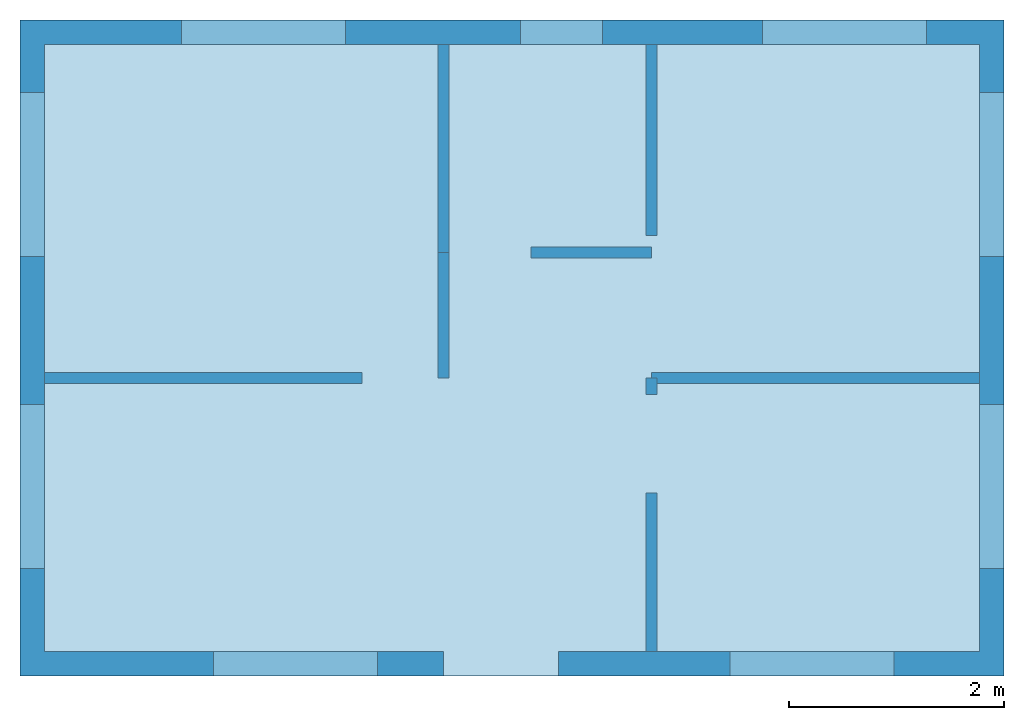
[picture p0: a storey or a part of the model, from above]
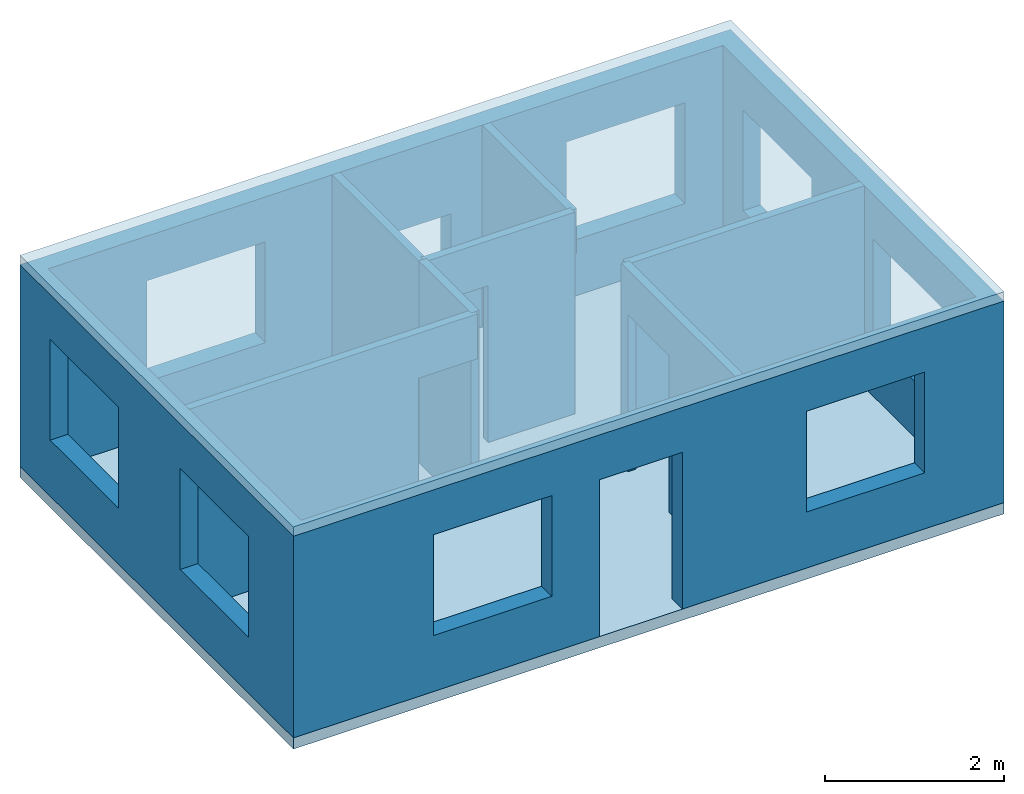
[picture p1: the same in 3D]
Properties of the parts of a building model (IFC4)

# File
Description: ViewDefinition [CoordinationView]
File name: HOUSE_FINAL_model2.ifc
Time: 2026-05-28T17:05:32
Written by: IfcOpenShell 0.8.4
Made in: IfcOpenShell 0.8.4

# IfcSite, Site_House
LongName: Site; RefLatitude: 0, 0, 0; RefLongitude: 0, 0, 0; RefElevation: 0 m

# IfcBuilding, Building_House
LongName: Building

# IfcBuildingStorey, Storey_Ground_Floor
In: Building_House
LongName: Storey_Ground_Floor

# IfcSpace (5)
In: Storey_Ground_Floor
PredefinedType: SPACE; ElevationWithFlooring: 179769313486231984327691555456465334352792049845835403698975498274516640839035331220428405233759257992518934458973701912372526858022072543307963267001224101383206867715061179627420854643452932421422530262411540848296933747097475316393099729687457046184498757783293606675351070501624177657401134563083681792 m
Name | LongName
Master Bedroom | Space
Toilet | Space001
Bedroom | Space002
Living Room | Space003
Kitchen | Space004

# IfcDoor (5)
In: Storey_Ground_Floor
OverallHeight: 2133.6 m; PredefinedType: DOOR; OperationType: SINGLE_SWING_LEFT
Name | OverallWidth (m)
Door_Main_Entrance | 1066.8
Door_Master_Bedroom | 914.4
Door_Toilet | 762
Door_Bedroom | 914.4
Door_Kitchen | 914.4

# IfcWall (8)
In: Storey_Ground_Floor
PredefinedType: MOVABLE
Name
Wall_Int_Master_Toilet
Wall_Int_Toilet_Bedroom
Wall_Int_Master_Living
Wall_Int_Bedroom_Kitchen
Wall_Int_Living_Kitchen
Wall_Int_Toilet_South
Wall_Int_Central_Partition
Wall_Ext_Perimeter

# IfcWindow (9)
In: Storey_Ground_Floor
PredefinedType: WINDOW; PartitioningType: SINGLE_PANEL
Name | OverallHeight (m) | OverallWidth (m)
Window_Master_North | 1371.6 | 1524
Window_Toilet_North | 914.4 | 762
Window_Bedroom_North | 1371.6 | 1524
Window_Master_West | 1371.6 | 1524
Window_Living_West | 1371.6 | 1524
Window_Bedroom_East | 1371.6 | 1524
Window_Kitchen_East | 1371.6 | 1524
Window_Living_South | 1371.6 | 1524
Window_Kitchen_South | 1371.6 | 1524
